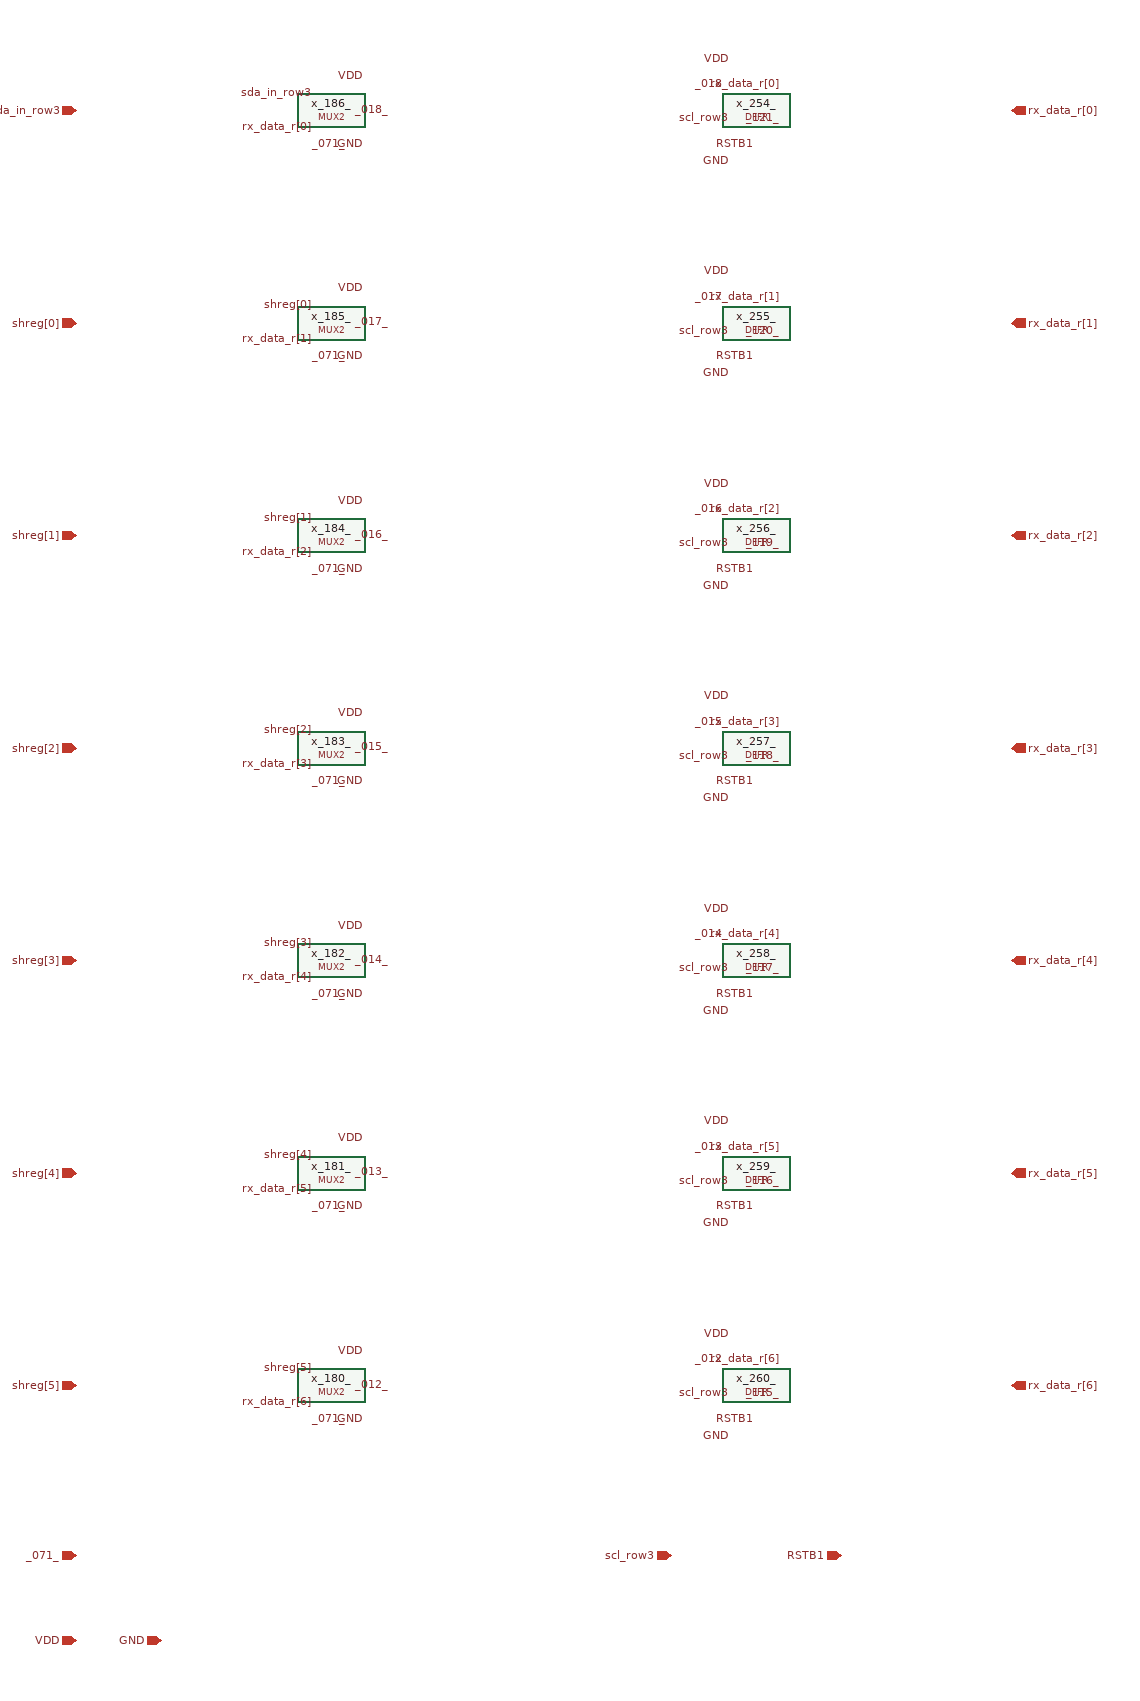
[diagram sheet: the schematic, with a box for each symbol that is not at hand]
v {xschem version=3.4.4 file_version=1.2
}
G {}
K {}
V {}
S {}
E {}
C {/Users/okamura/Dropbox/91_OpenPDK/TR-1um/libs.tech/xschem/TR-1um_5_stdcell/MUX2.sym} 0 0 0 0 {name=x_180_}
C {devices/lab_pin.sym} -20 -20 0 0 {name=l1 lab=shreg[5]}
C {devices/lab_pin.sym} -20 20 0 0 {name=l2 lab=rx_data_r[6]}
C {devices/lab_pin.sym} 20 40 0 0 {name=l3 lab=_071_}
C {devices/lab_pin.sym} 70 0 0 0 {name=l4 lab=_012_}
C {devices/lab_pin.sym} 40 -40 0 0 {name=l5 lab=VDD}
C {devices/lab_pin.sym} 40 40 0 0 {name=l6 lab=GND}
C {/Users/okamura/Dropbox/98_LSI_Design/TR-1um_Async_I2C/LEF/DFFR.sym} 500 0 0 0 {name=x_260_}
C {devices/lab_pin.sym} 470 -30 0 0 {name=l7 lab=_012_}
C {devices/lab_pin.sym} 530 -30 0 0 {name=l8 lab=rx_data_r[6]}
C {devices/lab_pin.sym} 530 10 0 0 {name=l9 lab=_115_}
C {devices/lab_pin.sym} 470 10 0 0 {name=l10 lab=scl_row3}
C {devices/lab_pin.sym} 500 40 0 0 {name=l11 lab=RSTB1}
C {devices/lab_pin.sym} 470 -60 0 0 {name=l12 lab=VDD}
C {devices/lab_pin.sym} 470 60 0 0 {name=l13 lab=GND}
C {devices/ipin.sym} -300 0 0 0 {name=io_A_0 lab=shreg[5]}
C {devices/opin.sym} 800 0 0 0 {name=io_Q_0 lab=rx_data_r[6]}
C {/Users/okamura/Dropbox/91_OpenPDK/TR-1um/libs.tech/xschem/TR-1um_5_stdcell/MUX2.sym} 0 -250 0 0 {name=x_181_}
C {devices/lab_pin.sym} -20 -270 0 0 {name=l14 lab=shreg[4]}
C {devices/lab_pin.sym} -20 -230 0 0 {name=l15 lab=rx_data_r[5]}
C {devices/lab_pin.sym} 20 -210 0 0 {name=l16 lab=_071_}
C {devices/lab_pin.sym} 70 -250 0 0 {name=l17 lab=_013_}
C {devices/lab_pin.sym} 40 -290 0 0 {name=l18 lab=VDD}
C {devices/lab_pin.sym} 40 -210 0 0 {name=l19 lab=GND}
C {/Users/okamura/Dropbox/98_LSI_Design/TR-1um_Async_I2C/LEF/DFFR.sym} 500 -250 0 0 {name=x_259_}
C {devices/lab_pin.sym} 470 -280 0 0 {name=l20 lab=_013_}
C {devices/lab_pin.sym} 530 -280 0 0 {name=l21 lab=rx_data_r[5]}
C {devices/lab_pin.sym} 530 -240 0 0 {name=l22 lab=_116_}
C {devices/lab_pin.sym} 470 -240 0 0 {name=l23 lab=scl_row3}
C {devices/lab_pin.sym} 500 -210 0 0 {name=l24 lab=RSTB1}
C {devices/lab_pin.sym} 470 -310 0 0 {name=l25 lab=VDD}
C {devices/lab_pin.sym} 470 -190 0 0 {name=l26 lab=GND}
C {devices/ipin.sym} -300 -250 0 0 {name=io_A_1 lab=shreg[4]}
C {devices/opin.sym} 800 -250 0 0 {name=io_Q_1 lab=rx_data_r[5]}
C {/Users/okamura/Dropbox/91_OpenPDK/TR-1um/libs.tech/xschem/TR-1um_5_stdcell/MUX2.sym} 0 -500 0 0 {name=x_182_}
C {devices/lab_pin.sym} -20 -520 0 0 {name=l27 lab=shreg[3]}
C {devices/lab_pin.sym} -20 -480 0 0 {name=l28 lab=rx_data_r[4]}
C {devices/lab_pin.sym} 20 -460 0 0 {name=l29 lab=_071_}
C {devices/lab_pin.sym} 70 -500 0 0 {name=l30 lab=_014_}
C {devices/lab_pin.sym} 40 -540 0 0 {name=l31 lab=VDD}
C {devices/lab_pin.sym} 40 -460 0 0 {name=l32 lab=GND}
C {/Users/okamura/Dropbox/98_LSI_Design/TR-1um_Async_I2C/LEF/DFFR.sym} 500 -500 0 0 {name=x_258_}
C {devices/lab_pin.sym} 470 -530 0 0 {name=l33 lab=_014_}
C {devices/lab_pin.sym} 530 -530 0 0 {name=l34 lab=rx_data_r[4]}
C {devices/lab_pin.sym} 530 -490 0 0 {name=l35 lab=_117_}
C {devices/lab_pin.sym} 470 -490 0 0 {name=l36 lab=scl_row3}
C {devices/lab_pin.sym} 500 -460 0 0 {name=l37 lab=RSTB1}
C {devices/lab_pin.sym} 470 -560 0 0 {name=l38 lab=VDD}
C {devices/lab_pin.sym} 470 -440 0 0 {name=l39 lab=GND}
C {devices/ipin.sym} -300 -500 0 0 {name=io_A_2 lab=shreg[3]}
C {devices/opin.sym} 800 -500 0 0 {name=io_Q_2 lab=rx_data_r[4]}
C {/Users/okamura/Dropbox/91_OpenPDK/TR-1um/libs.tech/xschem/TR-1um_5_stdcell/MUX2.sym} 0 -750 0 0 {name=x_183_}
C {devices/lab_pin.sym} -20 -770 0 0 {name=l40 lab=shreg[2]}
C {devices/lab_pin.sym} -20 -730 0 0 {name=l41 lab=rx_data_r[3]}
C {devices/lab_pin.sym} 20 -710 0 0 {name=l42 lab=_071_}
C {devices/lab_pin.sym} 70 -750 0 0 {name=l43 lab=_015_}
C {devices/lab_pin.sym} 40 -790 0 0 {name=l44 lab=VDD}
C {devices/lab_pin.sym} 40 -710 0 0 {name=l45 lab=GND}
C {/Users/okamura/Dropbox/98_LSI_Design/TR-1um_Async_I2C/LEF/DFFR.sym} 500 -750 0 0 {name=x_257_}
C {devices/lab_pin.sym} 470 -780 0 0 {name=l46 lab=_015_}
C {devices/lab_pin.sym} 530 -780 0 0 {name=l47 lab=rx_data_r[3]}
C {devices/lab_pin.sym} 530 -740 0 0 {name=l48 lab=_118_}
C {devices/lab_pin.sym} 470 -740 0 0 {name=l49 lab=scl_row3}
C {devices/lab_pin.sym} 500 -710 0 0 {name=l50 lab=RSTB1}
C {devices/lab_pin.sym} 470 -810 0 0 {name=l51 lab=VDD}
C {devices/lab_pin.sym} 470 -690 0 0 {name=l52 lab=GND}
C {devices/ipin.sym} -300 -750 0 0 {name=io_A_3 lab=shreg[2]}
C {devices/opin.sym} 800 -750 0 0 {name=io_Q_3 lab=rx_data_r[3]}
C {/Users/okamura/Dropbox/91_OpenPDK/TR-1um/libs.tech/xschem/TR-1um_5_stdcell/MUX2.sym} 0 -1000 0 0 {name=x_184_}
C {devices/lab_pin.sym} -20 -1020 0 0 {name=l53 lab=shreg[1]}
C {devices/lab_pin.sym} -20 -980 0 0 {name=l54 lab=rx_data_r[2]}
C {devices/lab_pin.sym} 20 -960 0 0 {name=l55 lab=_071_}
C {devices/lab_pin.sym} 70 -1000 0 0 {name=l56 lab=_016_}
C {devices/lab_pin.sym} 40 -1040 0 0 {name=l57 lab=VDD}
C {devices/lab_pin.sym} 40 -960 0 0 {name=l58 lab=GND}
C {/Users/okamura/Dropbox/98_LSI_Design/TR-1um_Async_I2C/LEF/DFFR.sym} 500 -1000 0 0 {name=x_256_}
C {devices/lab_pin.sym} 470 -1030 0 0 {name=l59 lab=_016_}
C {devices/lab_pin.sym} 530 -1030 0 0 {name=l60 lab=rx_data_r[2]}
C {devices/lab_pin.sym} 530 -990 0 0 {name=l61 lab=_119_}
C {devices/lab_pin.sym} 470 -990 0 0 {name=l62 lab=scl_row3}
C {devices/lab_pin.sym} 500 -960 0 0 {name=l63 lab=RSTB1}
C {devices/lab_pin.sym} 470 -1060 0 0 {name=l64 lab=VDD}
C {devices/lab_pin.sym} 470 -940 0 0 {name=l65 lab=GND}
C {devices/ipin.sym} -300 -1000 0 0 {name=io_A_4 lab=shreg[1]}
C {devices/opin.sym} 800 -1000 0 0 {name=io_Q_4 lab=rx_data_r[2]}
C {/Users/okamura/Dropbox/91_OpenPDK/TR-1um/libs.tech/xschem/TR-1um_5_stdcell/MUX2.sym} 0 -1250 0 0 {name=x_185_}
C {devices/lab_pin.sym} -20 -1270 0 0 {name=l66 lab=shreg[0]}
C {devices/lab_pin.sym} -20 -1230 0 0 {name=l67 lab=rx_data_r[1]}
C {devices/lab_pin.sym} 20 -1210 0 0 {name=l68 lab=_071_}
C {devices/lab_pin.sym} 70 -1250 0 0 {name=l69 lab=_017_}
C {devices/lab_pin.sym} 40 -1290 0 0 {name=l70 lab=VDD}
C {devices/lab_pin.sym} 40 -1210 0 0 {name=l71 lab=GND}
C {/Users/okamura/Dropbox/98_LSI_Design/TR-1um_Async_I2C/LEF/DFFR.sym} 500 -1250 0 0 {name=x_255_}
C {devices/lab_pin.sym} 470 -1280 0 0 {name=l72 lab=_017_}
C {devices/lab_pin.sym} 530 -1280 0 0 {name=l73 lab=rx_data_r[1]}
C {devices/lab_pin.sym} 530 -1240 0 0 {name=l74 lab=_120_}
C {devices/lab_pin.sym} 470 -1240 0 0 {name=l75 lab=scl_row3}
C {devices/lab_pin.sym} 500 -1210 0 0 {name=l76 lab=RSTB1}
C {devices/lab_pin.sym} 470 -1310 0 0 {name=l77 lab=VDD}
C {devices/lab_pin.sym} 470 -1190 0 0 {name=l78 lab=GND}
C {devices/ipin.sym} -300 -1250 0 0 {name=io_A_5 lab=shreg[0]}
C {devices/opin.sym} 800 -1250 0 0 {name=io_Q_5 lab=rx_data_r[1]}
C {/Users/okamura/Dropbox/91_OpenPDK/TR-1um/libs.tech/xschem/TR-1um_5_stdcell/MUX2.sym} 0 -1500 0 0 {name=x_186_}
C {devices/lab_pin.sym} -20 -1520 0 0 {name=l79 lab=sda_in_row3}
C {devices/lab_pin.sym} -20 -1480 0 0 {name=l80 lab=rx_data_r[0]}
C {devices/lab_pin.sym} 20 -1460 0 0 {name=l81 lab=_071_}
C {devices/lab_pin.sym} 70 -1500 0 0 {name=l82 lab=_018_}
C {devices/lab_pin.sym} 40 -1540 0 0 {name=l83 lab=VDD}
C {devices/lab_pin.sym} 40 -1460 0 0 {name=l84 lab=GND}
C {/Users/okamura/Dropbox/98_LSI_Design/TR-1um_Async_I2C/LEF/DFFR.sym} 500 -1500 0 0 {name=x_254_}
C {devices/lab_pin.sym} 470 -1530 0 0 {name=l85 lab=_018_}
C {devices/lab_pin.sym} 530 -1530 0 0 {name=l86 lab=rx_data_r[0]}
C {devices/lab_pin.sym} 530 -1490 0 0 {name=l87 lab=_121_}
C {devices/lab_pin.sym} 470 -1490 0 0 {name=l88 lab=scl_row3}
C {devices/lab_pin.sym} 500 -1460 0 0 {name=l89 lab=RSTB1}
C {devices/lab_pin.sym} 470 -1560 0 0 {name=l90 lab=VDD}
C {devices/lab_pin.sym} 470 -1440 0 0 {name=l91 lab=GND}
C {devices/ipin.sym} -300 -1500 0 0 {name=io_A_6 lab=sda_in_row3}
C {devices/opin.sym} 800 -1500 0 0 {name=io_Q_6 lab=rx_data_r[0]}
C {devices/ipin.sym} -300 200 0 0 {name=io_S lab=_071_}
C {devices/ipin.sym} 400 200 0 0 {name=io_CK lab=scl_row3}
C {devices/ipin.sym} 600 200 0 0 {name=io_RSTB lab=RSTB1}
C {devices/iopin.sym} -300 300 0 0 {name=io_VDD lab=VDD}
C {devices/iopin.sym} -200 300 0 0 {name=io_GND lab=GND}
